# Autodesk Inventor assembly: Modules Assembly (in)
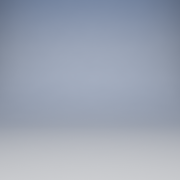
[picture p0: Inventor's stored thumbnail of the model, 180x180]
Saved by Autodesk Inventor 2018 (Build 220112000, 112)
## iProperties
Created: 2014-08
Part Number: Modules Assembly (in)
Document SubType Name: Assembly
Designer: Wally
Author: Wally
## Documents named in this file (1)
- D:\!!AutoCAD Modules!!\Templates\Inventor\English Templates\Modules Assembly (in).iam
